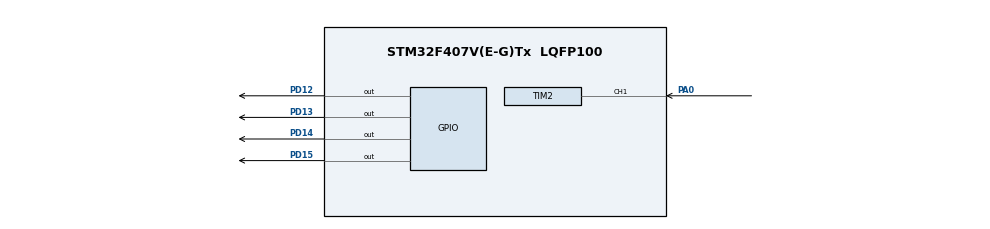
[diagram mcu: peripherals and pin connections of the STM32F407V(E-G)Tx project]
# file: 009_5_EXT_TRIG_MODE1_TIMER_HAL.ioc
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Mcu.Family=STM32F4
Mcu.Name=STM32F407V(E-G)Tx
Mcu.Package=LQFP100
NVIC.PriorityGroup=NVIC_PRIORITYGROUP_4
PA0-WKUP.Signal=S_TIM2_CH1_ETR
PD12.Signal=GPIO_Output
PD13.Signal=GPIO_Output
PD14.Signal=GPIO_Output
PD15.Signal=GPIO_Output
ProjectManager.HeapSize=0x200
ProjectManager.StackSize=0x400
ProjectManager.TargetToolchain=TrueSTUDIO
RCC.48MHZClocksFreq_Value=84000000
RCC.AHBFreq_Value=168000000
RCC.APB1CLKDivider=RCC_HCLK_DIV4
RCC.APB1Freq_Value=42000000
RCC.APB1TimFreq_Value=84000000
RCC.APB2CLKDivider=RCC_HCLK_DIV2
RCC.APB2Freq_Value=84000000
RCC.APB2TimFreq_Value=168000000
RCC.CortexFreq_Value=168000000
RCC.HCLKFreq_Value=168000000
RCC.HSE_VALUE=25000000
RCC.HSI_VALUE=16000000
RCC.LSE_VALUE=32768
RCC.PLLM=8
RCC.PLLN=168
RCC.SYSCLKFreq_VALUE=168000000
RCC.SYSCLKSource=RCC_SYSCLKSOURCE_PLLCLK
RCC.VCOOutputFreq_Value=336000000
SH.S_TIM2_CH1_ETR.0=TIM2_CH1,TriggerSource_TI1FP1
TIM2.Period=50
TIM2.Slave_TriggerFilter=15
VP_TIM2_VS_ControllerModeClock.Mode=Clock Mode
board=custom

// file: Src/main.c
/* USER CODE BEGIN Header */
/**
  ******************************************************************************
  * @file           : main.c
  * @brief          : Main program body
  ******************************************************************************
  * @attention
  *
  * <h2><center>&copy; Copyright (c) 2019 STMicroelectronics.
  * All rights reserved.</center></h2>
  *
  * This software component is licensed by ST under BSD 3-Clause license,
  * the "License"; You may not use this file except in compliance with the
  * License. You may obtain a copy of the License at:
  *                        opensource.org/licenses/BSD-3-Clause
  *
  ******************************************************************************
  */
/* USER CODE END Header */

#include "main.h"

TIM_HandleTypeDef htim2;

/* USER CODE BEGIN PV */
uint16_t count;
/* USER CODE END PV */

void SystemClock_Config(void);
static void MX_GPIO_Init(void);
static void MX_TIM2_Init(void);

int main(void)
{

  /* MCU Configuration--------------------------------------------------------*/

  /* Reset of all peripherals, Initializes the Flash interface and the Systick. */
  HAL_Init();

  /* Configure the system clock */
  SystemClock_Config();

  /* Initialize all configured peripherals */
  MX_GPIO_Init();
  MX_TIM2_Init();
  /* USER CODE BEGIN 2 */
  HAL_TIM_Base_Start(&htim2);
  /* USER CODE END 2 */

  /* Infinite loop */
  while (1)
  {

    /* USER CODE BEGIN 3 */
	  count = __HAL_TIM_GetCounter(&htim2);
  }
  /* USER CODE END 3 */
}

void SystemClock_Config(void)
{
  RCC_OscInitTypeDef RCC_OscInitStruct = {0};
  RCC_ClkInitTypeDef RCC_ClkInitStruct = {0};

  /** Configure the main internal regulator output voltage
  */
  __HAL_RCC_PWR_CLK_ENABLE();
  __HAL_PWR_VOLTAGESCALING_CONFIG(PWR_REGULATOR_VOLTAGE_SCALE1);
  /** Initializes the CPU, AHB and APB busses clocks
  */
  RCC_OscInitStruct.OscillatorType = RCC_OSCILLATORTYPE_HSI;
  RCC_OscInitStruct.HSIState = RCC_HSI_ON;
  RCC_OscInitStruct.HSICalibrationValue = RCC_HSICALIBRATION_DEFAULT;
  RCC_OscInitStruct.PLL.PLLState = RCC_PLL_NONE;
  if (HAL_RCC_OscConfig(&RCC_OscInitStruct) != HAL_OK)
  {
    Error_Handler();
  }
  /** Initializes the CPU, AHB and APB busses clocks
  */
  RCC_ClkInitStruct.ClockType = RCC_CLOCKTYPE_HCLK|RCC_CLOCKTYPE_SYSCLK
                              |RCC_CLOCKTYPE_PCLK1|RCC_CLOCKTYPE_PCLK2;
  RCC_ClkInitStruct.SYSCLKSource = RCC_SYSCLKSOURCE_HSI;
  RCC_ClkInitStruct.AHBCLKDivider = RCC_SYSCLK_DIV1;
  RCC_ClkInitStruct.APB1CLKDivider = RCC_HCLK_DIV1;
  RCC_ClkInitStruct.APB2CLKDivider = RCC_HCLK_DIV1;

  if (HAL_RCC_ClockConfig(&RCC_ClkInitStruct, FLASH_LATENCY_0) != HAL_OK)
  {
    Error_Handler();
  }
}

static void MX_TIM2_Init(void)
{

  TIM_SlaveConfigTypeDef sSlaveConfig = {0};
  TIM_MasterConfigTypeDef sMasterConfig = {0};

  htim2.Instance = TIM2;
  htim2.Init.Prescaler = 0;
  htim2.Init.CounterMode = TIM_COUNTERMODE_UP;
  htim2.Init.Period = 100;
  htim2.Init.ClockDivision = TIM_CLOCKDIVISION_DIV1;
  htim2.Init.AutoReloadPreload = TIM_AUTORELOAD_PRELOAD_DISABLE;
  if (HAL_TIM_Base_Init(&htim2) != HAL_OK)
  {
    Error_Handler();
  }
  sSlaveConfig.SlaveMode = TIM_SLAVEMODE_EXTERNAL1;
  sSlaveConfig.InputTrigger = TIM_TS_TI1FP1;
  sSlaveConfig.TriggerPolarity = TIM_TRIGGERPOLARITY_RISING;
  sSlaveConfig.TriggerFilter = 0;
  if (HAL_TIM_SlaveConfigSynchro(&htim2, &sSlaveConfig) != HAL_OK)
  {
    Error_Handler();
  }
  sMasterConfig.MasterOutputTrigger = TIM_TRGO_RESET;
  sMasterConfig.MasterSlaveMode = TIM_MASTERSLAVEMODE_DISABLE;
  if (HAL_TIMEx_MasterConfigSynchronization(&htim2, &sMasterConfig) != HAL_OK)
  {
    Error_Handler();
  }

}

static void MX_GPIO_Init(void)
{

  /* GPIO Ports Clock Enable */
  __HAL_RCC_GPIOA_CLK_ENABLE();

}

void Error_Handler(void)
{
}

/************************ (C) COPYRIGHT STMicroelectronics *****END OF FILE****/
